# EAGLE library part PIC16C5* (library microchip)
MICROCONTROLLER EPROM/ROM-based

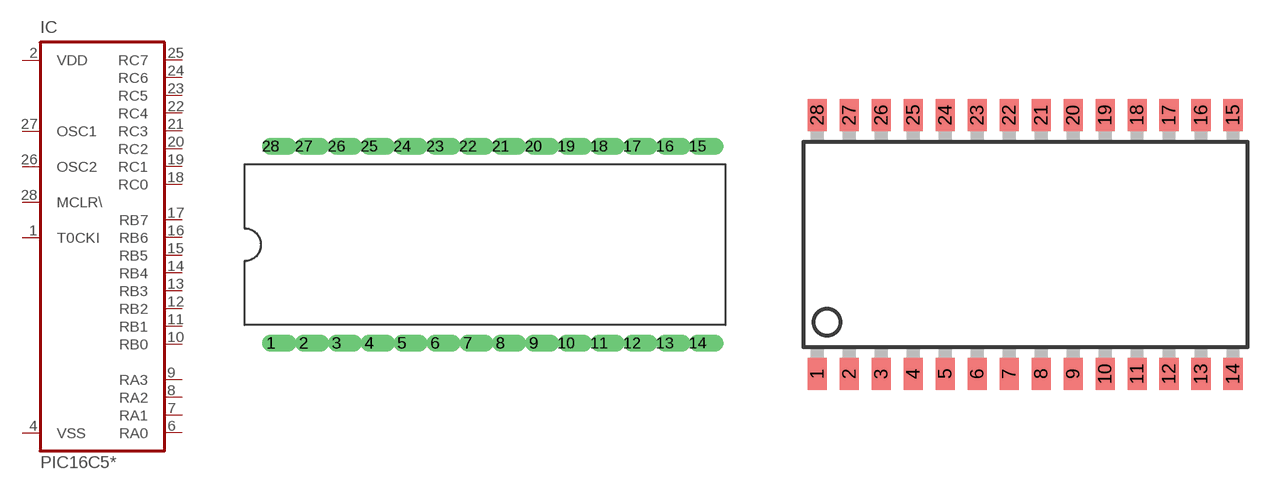
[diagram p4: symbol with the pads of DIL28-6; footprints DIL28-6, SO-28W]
Designator prefix IC

## PIC16C55P, PIC16C57P, PIC16C57AP  [DIL28-6]
1  T0CKI  in
2  VDD  pwr
3  NC  nc
4  VSS  pwr
5  NC  nc
6  RA0
7  RA1
8  RA2
9  RA3
10  RB0
11  RB1
12  RB2
13  RB3
14  RB4
15  RB5
16  RB6
17  RB7
18  RC0
19  RC1
20  RC2
21  RC3
22  RC4
23  RC5
24  RC6
25  RC7
26  OSC2  out
27  OSC1  in
28  MCLR\  in

## PIC16C55SO, PIC16C57SO, PIC16C57ASO  [SO-28W]
Pads as for DIL28-6

## PIC16C55SS, PIC16C57SS, PIC16C57ASS  [SSOP28]
Pads as for DIL28-6

## Footprint DIL28-6 (pad centres in mm)
Dual In Line package type P
drill 0.813 offset: 1 -16.51,-7.62; 2 -13.97,-7.62; 3 -11.43,-7.62; 4 -8.89,-7.62; 5 -6.35,-7.62; 6 -3.81,-7.62; 7 -1.27,-7.62; 8 1.27,-7.62; 9 3.81,-7.62; 10 6.35,-7.62; 11 8.89,-7.62; 12 11.43,-7.62; 13 13.97,-7.62; 14 16.51,-7.62; 15 16.51,7.62; 16 13.97,7.62; 17 11.43,7.62; 18 8.89,7.62; 19 6.35,7.62; 20 3.81,7.62; 21 1.27,7.62; 22 -1.27,7.62; 23 -3.81,7.62; 24 -6.35,7.62; 25 -8.89,7.62; 26 -11.43,7.62; 27 -13.97,7.62; 28 -16.51,7.62

## Footprint SO-28W (pad centres in mm)
Small Outline Wide Plastic Gull Wing 300-mil body, package type SO
smd 0.762 x 1.27: 1 -7.62,-5.207; 2 -6.35,-5.207; 3 -5.08,-5.207; 4 -3.81,-5.207; 5 -2.54,-5.207; 6 -1.27,-5.207; 7 0,-5.207; 8 1.27,-5.207; 9 2.54,-5.207; 10 3.81,-5.207; 11 5.08,-5.207; 12 6.35,-5.207; 13 7.62,-5.207; 14 8.89,-5.207; 15 8.89,5.08; 16 7.62,5.08; 17 6.35,5.08; 18 5.08,5.08; 19 3.81,5.08; 20 2.54,5.08; 21 1.27,5.08; 22 0,5.08; 23 -1.27,5.08; 24 -2.54,5.08; 25 -3.81,5.08; 26 -5.08,5.08; 27 -6.35,5.08; 28 -7.62,5.08

## Footprint SSOP28 (pad centres in mm)
Shrink Small Outline Package package type SS
smd 0.4 x 1.5: 1 -4.225,-3.625; 2 -3.575,-3.625; 3 -2.925,-3.625; 4 -2.275,-3.625; 5 -1.625,-3.625; 6 -0.975,-3.625; 7 -0.325,-3.625; 8 0.325,-3.625; 9 0.975,-3.625; 10 1.625,-3.625; 11 2.275,-3.625; 12 2.925,-3.625; 13 3.575,-3.625; 14 4.225,-3.625; 15 4.225,3.625; 16 3.575,3.625; 17 2.925,3.625; 18 2.275,3.625; 19 1.625,3.625; 20 0.975,3.625; 21 0.325,3.625; 22 -0.325,3.625; 23 -0.975,3.625; 24 -1.625,3.625; 25 -2.275,3.625; 26 -2.925,3.625; 27 -3.575,3.625; 28 -4.225,3.625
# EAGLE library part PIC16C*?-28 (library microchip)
MICROCONTROLLER 8-BitEPROM/ROM-based Pin compatible: PIC16CR62, PIC16C62A, PIC16C63, PIC16CR63 PIC16C66, PIC16C72, PIC16C73A, PIC16C76

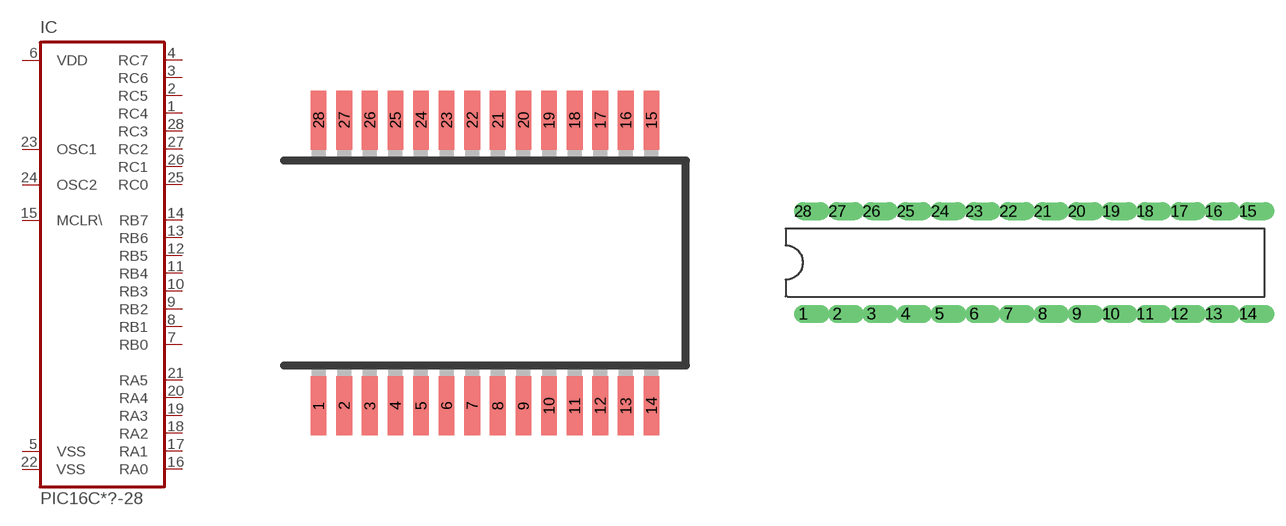
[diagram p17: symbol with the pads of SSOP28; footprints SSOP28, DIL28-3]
Designator prefix IC

## PIC16C62ASS-28, PIC16C63SS-28, PIC16C66SS-28, PIC16C72SS-28, PIC16C73ASS-28, PIC16C76SS-28, PIC16CR62SS-28, PIC16CR63SS-28  [SSOP28]
1  RC4
2  RC5
3  RC6
4  RC7
5  VSS  pwr
6  VDD  pwr
7  RB0
8  RB1
9  RB2
10  RB3
11  RB4
12  RB5
13  RB6
14  RB7
15  MCLR\  in
16  RA0
17  RA1
18  RA2
19  RA3
20  RA4
21  RA5
22  VSS  pwr
23  OSC1
24  OSC2
25  RC0
26  RC1
27  RC2
28  RC3

## PIC16C62AP-28, PIC16C63P-28, PIC16C66P-28, PIC16C72P-28, PIC16C73AP-28, PIC16C76P-28, PIC16CR62P-28, PIC16CR63P-28  [DIL28-3]
Pads as for SSOP28

## PIC16C62ASO-28, PIC16C63SO-28, PIC16C66SO-28, PIC16C72SO-28, PIC16C73ASO-28, PIC16C76SO-28, PIC16CR62SO-28, PIC16CR63SO-28  [SO-28W]
Pads as for SSOP28

## PIC16C62PS-28, PIC16C62APS-28, PIC16C63PS-28, PIC16C66PS-28, PIC16C72PS-28, PIC16C73APS-28, PIC16C76PS-28, PIC16CR63PS-28  [DIL28-3]
Pads as for SSOP28

## PIC16C62AJW-28, PIC16C63JW-28, PIC16C66JW-28, PIC16C72JW-28, PIC16C73AJW-28, PIC16C76JW-28, PIC16CR62JW-28, PIC16CR63JW-28  [DIL28-6]
Pads as for SSOP28

## Footprint SSOP28 (pad centres in mm)
Shrink Small Outline Package package type SS
smd 0.4 x 1.5: 1 -4.225,-3.625; 2 -3.575,-3.625; 3 -2.925,-3.625; 4 -2.275,-3.625; 5 -1.625,-3.625; 6 -0.975,-3.625; 7 -0.325,-3.625; 8 0.325,-3.625; 9 0.975,-3.625; 10 1.625,-3.625; 11 2.275,-3.625; 12 2.925,-3.625; 13 3.575,-3.625; 14 4.225,-3.625; 15 4.225,3.625; 16 3.575,3.625; 17 2.925,3.625; 18 2.275,3.625; 19 1.625,3.625; 20 0.975,3.625; 21 0.325,3.625; 22 -0.325,3.625; 23 -0.975,3.625; 24 -1.625,3.625; 25 -2.275,3.625; 26 -2.925,3.625; 27 -3.575,3.625; 28 -4.225,3.625

## Footprint DIL28-3 (pad centres in mm)
Dual In Line package type P
drill 0.813 offset: 1 -16.51,-3.81; 2 -13.97,-3.81; 3 -11.43,-3.81; 4 -8.89,-3.81; 5 -6.35,-3.81; 6 -3.81,-3.81; 7 -1.27,-3.81; 8 1.27,-3.81; 9 3.81,-3.81; 10 6.35,-3.81; 11 8.89,-3.81; 12 11.43,-3.81; 13 13.97,-3.81; 14 16.51,-3.81; 15 16.51,3.81; 16 13.97,3.81; 17 11.43,3.81; 18 8.89,3.81; 19 6.35,3.81; 20 3.81,3.81; 21 1.27,3.81; 22 -1.27,3.81; 23 -3.81,3.81; 24 -6.35,3.81; 25 -8.89,3.81; 26 -11.43,3.81; 27 -13.97,3.81; 28 -16.51,3.81

## Footprint SO-28W (pad centres in mm)
Small Outline Wide Plastic Gull Wing 300-mil body, package type SO
smd 0.762 x 1.27: 1 -7.62,-5.207; 2 -6.35,-5.207; 3 -5.08,-5.207; 4 -3.81,-5.207; 5 -2.54,-5.207; 6 -1.27,-5.207; 7 0,-5.207; 8 1.27,-5.207; 9 2.54,-5.207; 10 3.81,-5.207; 11 5.08,-5.207; 12 6.35,-5.207; 13 7.62,-5.207; 14 8.89,-5.207; 15 8.89,5.08; 16 7.62,5.08; 17 6.35,5.08; 18 5.08,5.08; 19 3.81,5.08; 20 2.54,5.08; 21 1.27,5.08; 22 0,5.08; 23 -1.27,5.08; 24 -2.54,5.08; 25 -3.81,5.08; 26 -5.08,5.08; 27 -6.35,5.08; 28 -7.62,5.08

## Footprint DIL28-6 (pad centres in mm)
Dual In Line package type P
drill 0.813 offset: 1 -16.51,-7.62; 2 -13.97,-7.62; 3 -11.43,-7.62; 4 -8.89,-7.62; 5 -6.35,-7.62; 6 -3.81,-7.62; 7 -1.27,-7.62; 8 1.27,-7.62; 9 3.81,-7.62; 10 6.35,-7.62; 11 8.89,-7.62; 12 11.43,-7.62; 13 13.97,-7.62; 14 16.51,-7.62; 15 16.51,7.62; 16 13.97,7.62; 17 11.43,7.62; 18 8.89,7.62; 19 6.35,7.62; 20 3.81,7.62; 21 1.27,7.62; 22 -1.27,7.62; 23 -3.81,7.62; 24 -6.35,7.62; 25 -8.89,7.62; 26 -11.43,7.62; 27 -13.97,7.62; 28 -16.51,7.62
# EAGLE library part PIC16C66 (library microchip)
MICROCONTROLLER

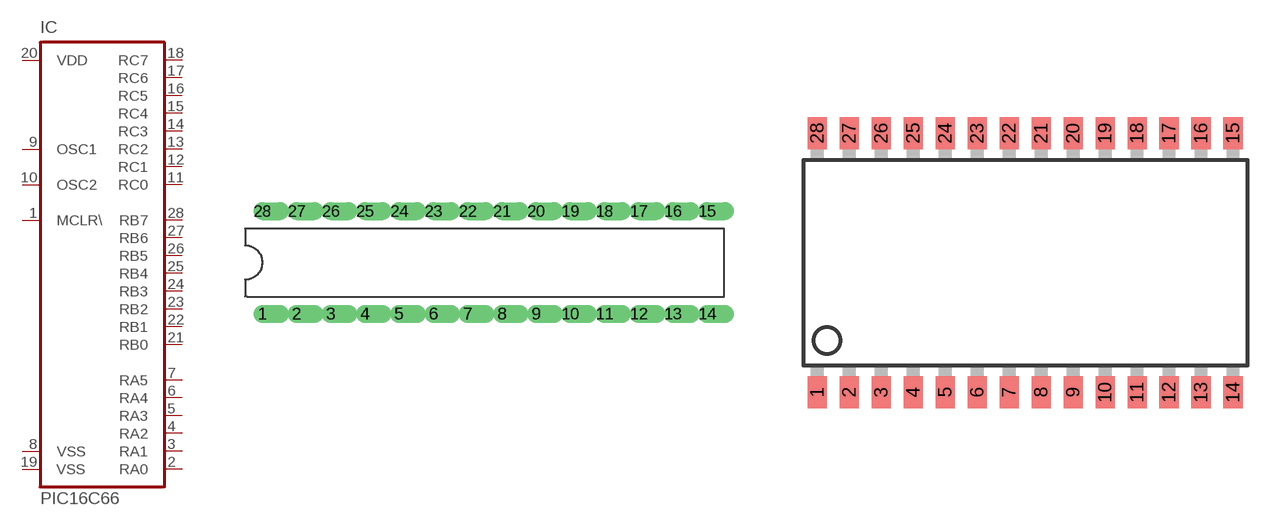
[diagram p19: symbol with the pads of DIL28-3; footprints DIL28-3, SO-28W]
Designator prefix IC

## PIC16C66P  [DIL28-3]
1  MCLR\  in
2  RA0
3  RA1
4  RA2
5  RA3
6  RA4
7  RA5
8  VSS  pwr
9  OSC1
10  OSC2
11  RC0
12  RC1
13  RC2
14  RC3
15  RC4
16  RC5
17  RC6
18  RC7
19  VSS  pwr
20  VDD  pwr
21  RB0
22  RB1
23  RB2
24  RB3
25  RB4
26  RB5
27  RB6
28  RB7

## PIC16C66SO  [SO-28W]
Pads as for DIL28-3

## PIC16C66JW  [DIL28-6]
Pads as for DIL28-3

## Footprint DIL28-3 (pad centres in mm)
Dual In Line package type P
drill 0.813 offset: 1 -16.51,-3.81; 2 -13.97,-3.81; 3 -11.43,-3.81; 4 -8.89,-3.81; 5 -6.35,-3.81; 6 -3.81,-3.81; 7 -1.27,-3.81; 8 1.27,-3.81; 9 3.81,-3.81; 10 6.35,-3.81; 11 8.89,-3.81; 12 11.43,-3.81; 13 13.97,-3.81; 14 16.51,-3.81; 15 16.51,3.81; 16 13.97,3.81; 17 11.43,3.81; 18 8.89,3.81; 19 6.35,3.81; 20 3.81,3.81; 21 1.27,3.81; 22 -1.27,3.81; 23 -3.81,3.81; 24 -6.35,3.81; 25 -8.89,3.81; 26 -11.43,3.81; 27 -13.97,3.81; 28 -16.51,3.81

## Footprint SO-28W (pad centres in mm)
Small Outline Wide Plastic Gull Wing 300-mil body, package type SO
smd 0.762 x 1.27: 1 -7.62,-5.207; 2 -6.35,-5.207; 3 -5.08,-5.207; 4 -3.81,-5.207; 5 -2.54,-5.207; 6 -1.27,-5.207; 7 0,-5.207; 8 1.27,-5.207; 9 2.54,-5.207; 10 3.81,-5.207; 11 5.08,-5.207; 12 6.35,-5.207; 13 7.62,-5.207; 14 8.89,-5.207; 15 8.89,5.08; 16 7.62,5.08; 17 6.35,5.08; 18 5.08,5.08; 19 3.81,5.08; 20 2.54,5.08; 21 1.27,5.08; 22 0,5.08; 23 -1.27,5.08; 24 -2.54,5.08; 25 -3.81,5.08; 26 -5.08,5.08; 27 -6.35,5.08; 28 -7.62,5.08

## Footprint DIL28-6 (pad centres in mm)
Dual In Line package type P
drill 0.813 offset: 1 -16.51,-7.62; 2 -13.97,-7.62; 3 -11.43,-7.62; 4 -8.89,-7.62; 5 -6.35,-7.62; 6 -3.81,-7.62; 7 -1.27,-7.62; 8 1.27,-7.62; 9 3.81,-7.62; 10 6.35,-7.62; 11 8.89,-7.62; 12 11.43,-7.62; 13 13.97,-7.62; 14 16.51,-7.62; 15 16.51,7.62; 16 13.97,7.62; 17 11.43,7.62; 18 8.89,7.62; 19 6.35,7.62; 20 3.81,7.62; 21 1.27,7.62; 22 -1.27,7.62; 23 -3.81,7.62; 24 -6.35,7.62; 25 -8.89,7.62; 26 -11.43,7.62; 27 -13.97,7.62; 28 -16.51,7.62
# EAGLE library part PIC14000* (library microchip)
MIXED SIGNAL CONTROLLER

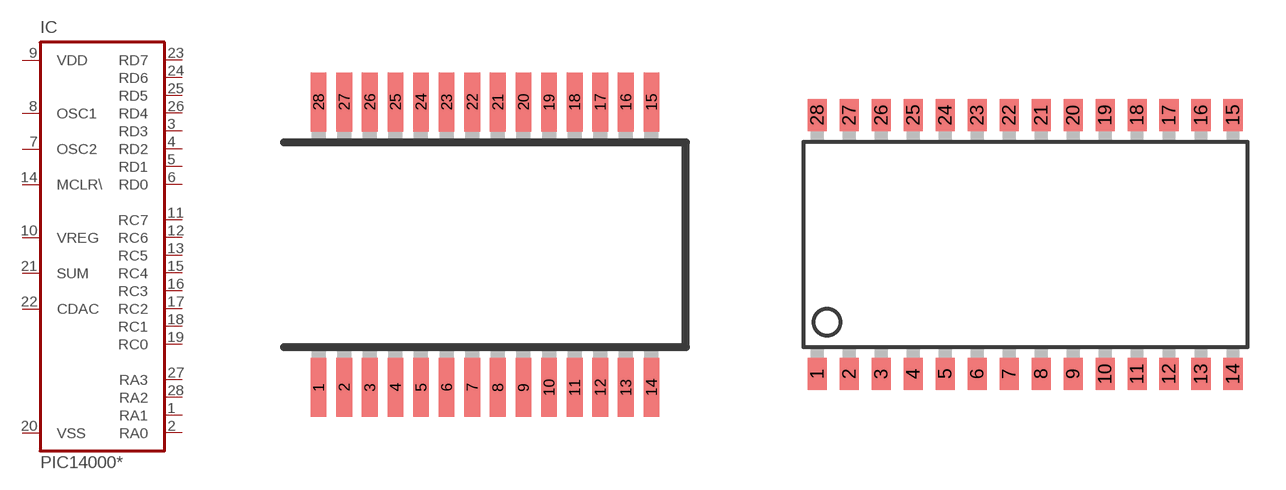
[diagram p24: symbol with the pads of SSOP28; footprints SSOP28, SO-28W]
Designator prefix IC

## PIC14000SS  [SSOP28]
1  RA1
2  RA0
3  RD3
4  RD2
5  RD1
6  RD0
7  OSC2  out
8  OSC1  in
9  VDD  pwr
10  VREG  out
11  RC7
12  RC6
13  RC5
14  MCLR\  in
15  RC4
16  RC3
17  RC2
18  RC1
19  RC0
20  VSS  pwr
21  SUM  out
22  CDAC  out
23  RD7
24  RD6
25  RD5
26  RD4
27  RA3
28  RA2

## PIC14000SO  [SO-28W]
Pads as for SSOP28

## PIC14000SP  [DIL28-3]
Pads as for SSOP28

## PIC14000JW  [DIL28-6]
Pads as for SSOP28

## Footprint SSOP28 (pad centres in mm)
Shrink Small Outline Package package type SS
smd 0.4 x 1.5: 1 -4.225,-3.625; 2 -3.575,-3.625; 3 -2.925,-3.625; 4 -2.275,-3.625; 5 -1.625,-3.625; 6 -0.975,-3.625; 7 -0.325,-3.625; 8 0.325,-3.625; 9 0.975,-3.625; 10 1.625,-3.625; 11 2.275,-3.625; 12 2.925,-3.625; 13 3.575,-3.625; 14 4.225,-3.625; 15 4.225,3.625; 16 3.575,3.625; 17 2.925,3.625; 18 2.275,3.625; 19 1.625,3.625; 20 0.975,3.625; 21 0.325,3.625; 22 -0.325,3.625; 23 -0.975,3.625; 24 -1.625,3.625; 25 -2.275,3.625; 26 -2.925,3.625; 27 -3.575,3.625; 28 -4.225,3.625

## Footprint SO-28W (pad centres in mm)
Small Outline Wide Plastic Gull Wing 300-mil body, package type SO
smd 0.762 x 1.27: 1 -7.62,-5.207; 2 -6.35,-5.207; 3 -5.08,-5.207; 4 -3.81,-5.207; 5 -2.54,-5.207; 6 -1.27,-5.207; 7 0,-5.207; 8 1.27,-5.207; 9 2.54,-5.207; 10 3.81,-5.207; 11 5.08,-5.207; 12 6.35,-5.207; 13 7.62,-5.207; 14 8.89,-5.207; 15 8.89,5.08; 16 7.62,5.08; 17 6.35,5.08; 18 5.08,5.08; 19 3.81,5.08; 20 2.54,5.08; 21 1.27,5.08; 22 0,5.08; 23 -1.27,5.08; 24 -2.54,5.08; 25 -3.81,5.08; 26 -5.08,5.08; 27 -6.35,5.08; 28 -7.62,5.08

## Footprint DIL28-3 (pad centres in mm)
Dual In Line package type P
drill 0.813 offset: 1 -16.51,-3.81; 2 -13.97,-3.81; 3 -11.43,-3.81; 4 -8.89,-3.81; 5 -6.35,-3.81; 6 -3.81,-3.81; 7 -1.27,-3.81; 8 1.27,-3.81; 9 3.81,-3.81; 10 6.35,-3.81; 11 8.89,-3.81; 12 11.43,-3.81; 13 13.97,-3.81; 14 16.51,-3.81; 15 16.51,3.81; 16 13.97,3.81; 17 11.43,3.81; 18 8.89,3.81; 19 6.35,3.81; 20 3.81,3.81; 21 1.27,3.81; 22 -1.27,3.81; 23 -3.81,3.81; 24 -6.35,3.81; 25 -8.89,3.81; 26 -11.43,3.81; 27 -13.97,3.81; 28 -16.51,3.81

## Footprint DIL28-6 (pad centres in mm)
Dual In Line package type P
drill 0.813 offset: 1 -16.51,-7.62; 2 -13.97,-7.62; 3 -11.43,-7.62; 4 -8.89,-7.62; 5 -6.35,-7.62; 6 -3.81,-7.62; 7 -1.27,-7.62; 8 1.27,-7.62; 9 3.81,-7.62; 10 6.35,-7.62; 11 8.89,-7.62; 12 11.43,-7.62; 13 13.97,-7.62; 14 16.51,-7.62; 15 16.51,7.62; 16 13.97,7.62; 17 11.43,7.62; 18 8.89,7.62; 19 6.35,7.62; 20 3.81,7.62; 21 1.27,7.62; 22 -1.27,7.62; 23 -3.81,7.62; 24 -6.35,7.62; 25 -8.89,7.62; 26 -11.43,7.62; 27 -13.97,7.62; 28 -16.51,7.62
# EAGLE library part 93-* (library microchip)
Serial EEPROM 512 x 8 bit/256 x 16 bit/1 K/4 K, 5.0 V, Microwire

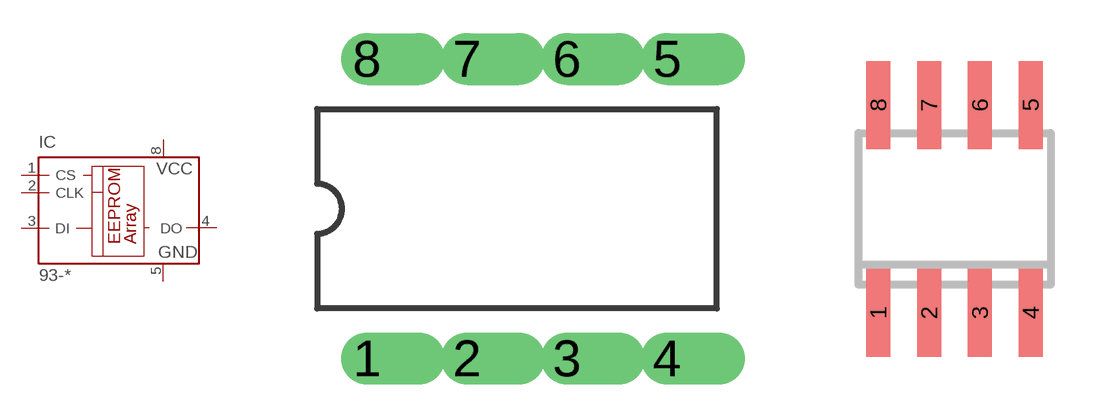
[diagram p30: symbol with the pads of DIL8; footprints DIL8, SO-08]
Designator prefix IC

## 93-C46AP, 93-C46BP, 93-C56AP, 93-C56BP, 93-C66AP, 93-C66BP, 93-LC56AP, 93-LC56BP  [DIL8]
1  CS  in
2  CLK  in
3  DI  in
4  DO  hiz
5  GND  pwr
8  VCC  pwr

## 93-C46ASN, 93-C46BSN, 93-C56ASN, 93-C56BSN, 93-C66ASN, 93-C66BSN, 93-LC56ASN, 93-LC56BSN  [SO-08]
Pads as for DIL8

## 93-C46AST, 93-C46BST, 93-LC56AST, 93-LC56BST  [TSSOP8]
Pads as for DIL8

## 93-C46ASM, 93-C46BSM, 93-LC56ASM, 93-LC56BSM  [SO-08M]
Pads as for DIL8

## Footprint DIL8 (pad centres in mm)
Dual In Line package type P
drill 0.813 offset: 1 -3.81,-3.81; 2 -1.27,-3.81; 3 1.27,-3.81; 4 3.81,-3.81; 5 3.81,3.81; 6 1.27,3.81; 7 -1.27,3.81; 8 -3.81,3.81

## Footprint SO-08 (pad centres in mm)
Small Outline Narrow Plastic Gull Wing 150-mil body, package type SN
smd 0.6 x 2.2: 1 -1.905,-2.6; 2 -0.635,-2.6; 3 0.635,-2.6; 4 1.905,-2.6; 5 1.905,2.6; 6 0.635,2.6; 7 -0.635,2.6; 8 -1.905,2.6

## Footprint TSSOP8 (pad centres in mm)
Thin Shrink Small Outline Package package type ST
smd 0.35 x 1.2: 1 -0.975,-2.925; 2 -0.325,-2.925; 3 0.325,-2.925; 4 0.975,-2.925; 5 0.975,2.925; 6 0.325,2.925; 7 -0.325,2.925; 8 -0.975,2.925

## Footprint SO-08M (pad centres in mm)
Small Outline Medium Plastic Gull Wing 207-mil body, package type SM
smd 0.6 x 2.2: 1 -1.905,-3.33; 2 -0.635,-3.33; 3 0.635,-3.33; 4 1.905,-3.33; 5 1.905,3.33; 6 0.635,3.33; 7 -0.635,3.33; 8 -1.905,3.33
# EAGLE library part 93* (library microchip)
Serial EPROM 1 K/2 K/4 K, low voltage, Microwire

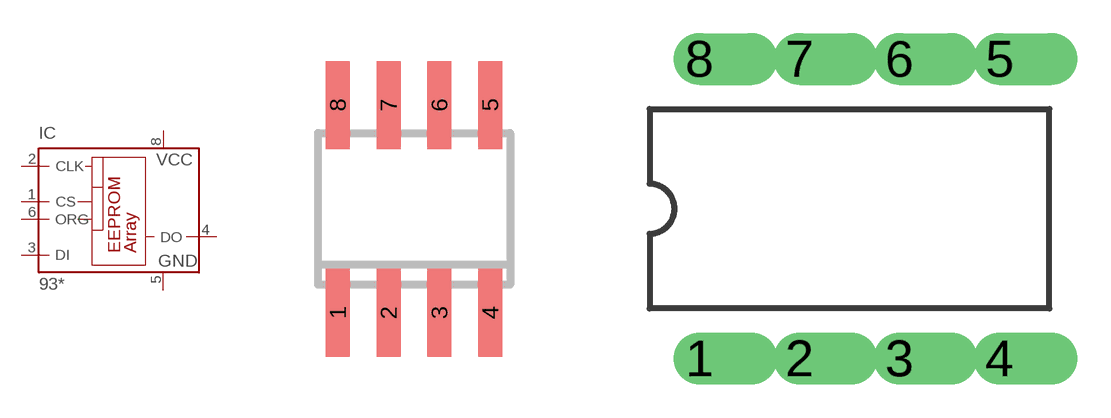
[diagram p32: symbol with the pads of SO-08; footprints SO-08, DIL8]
Designator prefix IC

## 93AA46SN, 93AA56SN, 93AA66SN, 93LC45SN, 93LC46SN, 93LC66SN  [SO-08]
1  CS  in
2  CLK  in
3  DI  in
4  DO  hiz
5  GND  pwr
6  ORG  in
7  NU  pas
8  VCC  pwr

## 93AA46P, 93AA56P, 93AA66P, 93LC46P, 93LC56P, 93LC66P  [DIL8]
Pads as for SO-08

## 93AA46SM, 93AA56SM, 93AA66SM, 93LC46SM, 93LC56SM, 93LC66SM  [SO-08M]
Pads as for SO-08

## 93LC46ST, 93LC56ST, 93LC66ST  [TSSOP8]
Pads as for SO-08

## Footprint SO-08 (pad centres in mm)
Small Outline Narrow Plastic Gull Wing 150-mil body, package type SN
smd 0.6 x 2.2: 1 -1.905,-2.6; 2 -0.635,-2.6; 3 0.635,-2.6; 4 1.905,-2.6; 5 1.905,2.6; 6 0.635,2.6; 7 -0.635,2.6; 8 -1.905,2.6

## Footprint DIL8 (pad centres in mm)
Dual In Line package type P
drill 0.813 offset: 1 -3.81,-3.81; 2 -1.27,-3.81; 3 1.27,-3.81; 4 3.81,-3.81; 5 3.81,3.81; 6 1.27,3.81; 7 -1.27,3.81; 8 -3.81,3.81

## Footprint SO-08M (pad centres in mm)
Small Outline Medium Plastic Gull Wing 207-mil body, package type SM
smd 0.6 x 2.2: 1 -1.905,-3.33; 2 -0.635,-3.33; 3 0.635,-3.33; 4 1.905,-3.33; 5 1.905,3.33; 6 0.635,3.33; 7 -0.635,3.33; 8 -1.905,3.33

## Footprint TSSOP8 (pad centres in mm)
Thin Shrink Small Outline Package package type ST
smd 0.35 x 1.2: 1 -0.975,-2.925; 2 -0.325,-2.925; 3 0.325,-2.925; 4 0.975,-2.925; 5 0.975,2.925; 6 0.325,2.925; 7 -0.325,2.925; 8 -0.975,2.925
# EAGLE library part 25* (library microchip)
Serial EEPROM 4 K, SPI bus

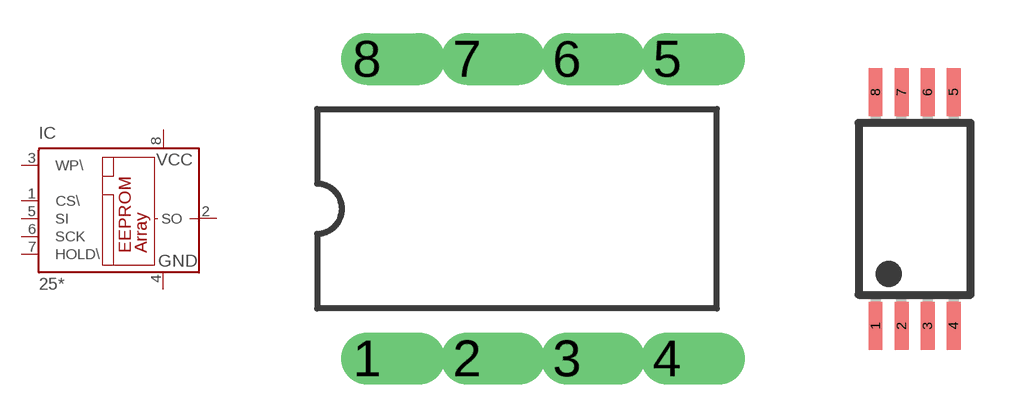
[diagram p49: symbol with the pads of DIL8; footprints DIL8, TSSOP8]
Designator prefix IC

## 25AA040P, 25AA080P, 25C040P, 25C080P, 25LC040P, 25LC080P  [DIL8]
1  CS\  in
2  SO
3  WP\  in
4  GND  pwr
5  SI  in
6  SCK  in
7  HOLD\  in
8  VCC  pwr

## 25AA040ST, 25C040ST, 25LC040ST  [TSSOP8]
Pads as for DIL8

## 25AA080SN, 25C080SN, 25LC080SN  [SO-08]
Pads as for DIL8

## Footprint DIL8 (pad centres in mm)
Dual In Line package type P
drill 0.813 offset: 1 -3.81,-3.81; 2 -1.27,-3.81; 3 1.27,-3.81; 4 3.81,-3.81; 5 3.81,3.81; 6 1.27,3.81; 7 -1.27,3.81; 8 -3.81,3.81

## Footprint TSSOP8 (pad centres in mm)
Thin Shrink Small Outline Package package type ST
smd 0.35 x 1.2: 1 -0.975,-2.925; 2 -0.325,-2.925; 3 0.325,-2.925; 4 0.975,-2.925; 5 0.975,2.925; 6 0.325,2.925; 7 -0.325,2.925; 8 -0.975,2.925

## Footprint SO-08 (pad centres in mm)
Small Outline Narrow Plastic Gull Wing 150-mil body, package type SN
smd 0.6 x 2.2: 1 -1.905,-2.6; 2 -0.635,-2.6; 3 0.635,-2.6; 4 1.905,-2.6; 5 1.905,2.6; 6 0.635,2.6; 7 -0.635,2.6; 8 -1.905,2.6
